VERSION 5.7 ;
  NOWIREEXTENSIONATPIN ON ;
  DIVIDERCHAR "/" ;
  BUSBITCHARS "[]" ;
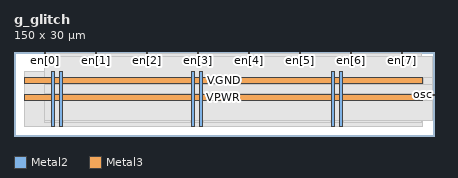
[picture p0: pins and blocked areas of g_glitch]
MACRO g_glitch
  CLASS BLOCK ;
  FOREIGN g_glitch ;
  ORIGIN 0.000 0.000 ;
  SIZE 150.000 BY 30.000 ;
  PIN VGND
    DIRECTION INOUT ;
    USE GROUND ;
    PORT
      LAYER Metal2 ;
        RECT 16.340 3.560 17.340 22.900 ;
    END
    PORT
      LAYER Metal2 ;
        RECT 66.340 3.560 67.340 22.900 ;
    END
    PORT
      LAYER Metal2 ;
        RECT 116.340 3.560 117.340 22.900 ;
    END
    PORT
      LAYER Metal3 ;
        RECT 3.840 18.780 145.920 20.780 ;
    END
  END VGND
  PIN VPWR
    DIRECTION INOUT ;
    USE POWER ;
    PORT
      LAYER Metal2 ;
        RECT 13.340 3.560 14.340 22.900 ;
    END
    PORT
      LAYER Metal2 ;
        RECT 63.340 3.560 64.340 22.900 ;
    END
    PORT
      LAYER Metal2 ;
        RECT 113.340 3.560 114.340 22.900 ;
    END
    PORT
      LAYER Metal3 ;
        RECT 3.840 12.780 145.920 14.780 ;
    END
  END VPWR
  PIN en[0]
    DIRECTION INPUT ;
    USE SIGNAL ;
    ANTENNAGATEAREA 0.180700 ;
    PORT
      LAYER Metal2 ;
        RECT 10.840 29.600 11.240 30.000 ;
    END
  END en[0]
  PIN en[1]
    DIRECTION INPUT ;
    USE SIGNAL ;
    ANTENNAGATEAREA 0.180700 ;
    PORT
      LAYER Metal2 ;
        RECT 29.080 29.600 29.480 30.000 ;
    END
  END en[1]
  PIN en[2]
    DIRECTION INPUT ;
    USE SIGNAL ;
    ANTENNAGATEAREA 0.180700 ;
    PORT
      LAYER Metal2 ;
        RECT 47.320 29.600 47.720 30.000 ;
    END
  END en[2]
  PIN en[3]
    DIRECTION INPUT ;
    USE SIGNAL ;
    ANTENNAGATEAREA 0.180700 ;
    PORT
      LAYER Metal2 ;
        RECT 65.560 29.600 65.960 30.000 ;
    END
  END en[3]
  PIN en[4]
    DIRECTION INPUT ;
    USE SIGNAL ;
    ANTENNAGATEAREA 0.180700 ;
    PORT
      LAYER Metal2 ;
        RECT 83.800 29.600 84.200 30.000 ;
    END
  END en[4]
  PIN en[5]
    DIRECTION INPUT ;
    USE SIGNAL ;
    ANTENNAGATEAREA 0.180700 ;
    PORT
      LAYER Metal2 ;
        RECT 102.040 29.600 102.440 30.000 ;
    END
  END en[5]
  PIN en[6]
    DIRECTION INPUT ;
    USE SIGNAL ;
    ANTENNAGATEAREA 0.180700 ;
    PORT
      LAYER Metal2 ;
        RECT 120.280 29.600 120.680 30.000 ;
    END
  END en[6]
  PIN en[7]
    DIRECTION INPUT ;
    USE SIGNAL ;
    ANTENNAGATEAREA 0.180700 ;
    PORT
      LAYER Metal2 ;
        RECT 138.520 29.600 138.920 30.000 ;
    END
  END en[7]
  PIN osc
    DIRECTION INPUT ;
    USE SIGNAL ;
    ANTENNAGATEAREA 0.180700 ;
    PORT
      LAYER Metal3 ;
        RECT 149.600 14.500 150.000 14.900 ;
    END
  END osc
  OBS
      LAYER GatPoly ;
        RECT 3.840 3.630 145.920 22.830 ;
      LAYER Metal1 ;
        RECT 3.840 3.560 145.920 22.900 ;
      LAYER Metal2 ;
        RECT 11.450 29.390 28.870 29.600 ;
        RECT 29.690 29.390 47.110 29.600 ;
        RECT 47.930 29.390 65.350 29.600 ;
        RECT 66.170 29.390 83.590 29.600 ;
        RECT 84.410 29.390 101.830 29.600 ;
        RECT 102.650 29.390 120.070 29.600 ;
        RECT 120.890 29.390 138.310 29.600 ;
        RECT 139.130 29.390 145.545 29.600 ;
        RECT 10.935 23.110 145.545 29.390 ;
        RECT 10.935 4.890 13.130 23.110 ;
        RECT 14.550 4.890 16.130 23.110 ;
        RECT 17.550 4.890 63.130 23.110 ;
        RECT 64.550 4.890 66.130 23.110 ;
        RECT 67.550 4.890 113.130 23.110 ;
        RECT 114.550 4.890 116.130 23.110 ;
        RECT 117.550 4.890 145.545 23.110 ;
      LAYER Metal3 ;
        RECT 10.895 20.990 149.600 28.240 ;
        RECT 146.130 18.570 149.600 20.990 ;
        RECT 10.895 15.110 149.600 18.570 ;
        RECT 10.895 14.990 149.390 15.110 ;
        RECT 146.130 14.290 149.390 14.990 ;
        RECT 146.130 12.570 149.600 14.290 ;
        RECT 10.895 5.360 149.600 12.570 ;
  END
END g_glitch
END LIBRARY

